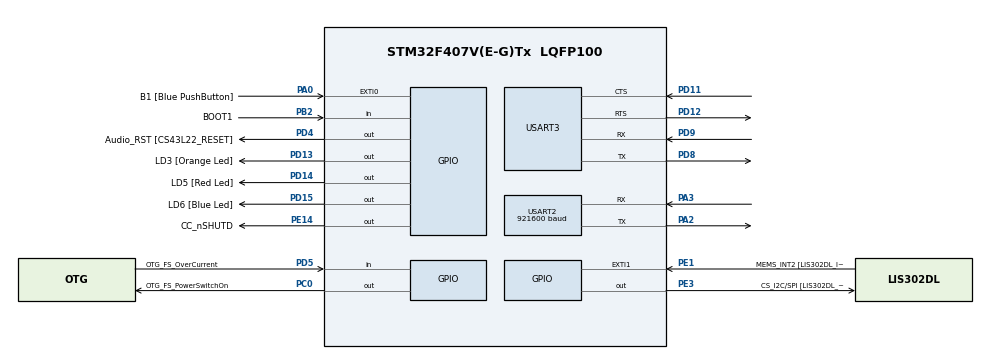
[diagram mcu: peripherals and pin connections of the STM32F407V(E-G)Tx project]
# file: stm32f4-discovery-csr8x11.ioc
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Dma.Request0=USART3_RX
Dma.Request1=USART3_TX
Dma.USART3_RX.0.Direction=DMA_PERIPH_TO_MEMORY
Dma.USART3_RX.0.FIFOMode=DMA_FIFOMODE_DISABLE
Dma.USART3_RX.0.Instance=DMA1_Stream1
Dma.USART3_RX.0.MemDataAlignment=DMA_MDATAALIGN_BYTE
Dma.USART3_RX.0.MemInc=DMA_MINC_ENABLE
Dma.USART3_RX.0.Mode=DMA_NORMAL
Dma.USART3_RX.0.PeriphDataAlignment=DMA_PDATAALIGN_BYTE
Dma.USART3_RX.0.PeriphInc=DMA_PINC_DISABLE
Dma.USART3_RX.0.Priority=DMA_PRIORITY_VERY_HIGH
Dma.USART3_TX.1.Direction=DMA_MEMORY_TO_PERIPH
Dma.USART3_TX.1.FIFOMode=DMA_FIFOMODE_DISABLE
Dma.USART3_TX.1.Instance=DMA1_Stream4
Dma.USART3_TX.1.MemDataAlignment=DMA_MDATAALIGN_BYTE
Dma.USART3_TX.1.MemInc=DMA_MINC_ENABLE
Dma.USART3_TX.1.Mode=DMA_NORMAL
Dma.USART3_TX.1.PeriphDataAlignment=DMA_PDATAALIGN_BYTE
Dma.USART3_TX.1.PeriphInc=DMA_PINC_DISABLE
Dma.USART3_TX.1.Priority=DMA_PRIORITY_MEDIUM
Mcu.Family=STM32F4
Mcu.Name=STM32F407V(E-G)Tx
Mcu.Package=LQFP100
NVIC.DMA1_Stream1_IRQn=true\:0\:0\:true\:false\:true\:true\:true
NVIC.DMA1_Stream4_IRQn=true\:0\:0\:false\:false\:true\:false\:true
NVIC.PriorityGroup=NVIC_PRIORITYGROUP_4
NVIC.USART2_IRQn=true\:15\:0\:true\:false\:true\:true\:true
NVIC.USART3_IRQn=true\:1\:0\:true\:false\:true\:true\:true
PA0-WKUP.GPIO_Label=B1 [Blue PushButton]
PA0-WKUP.GPIO_ModeDefaultEXTI=GPIO_MODE_EVT_RISING
PA0-WKUP.GPIO_PuPd=GPIO_NOPULL
PA0-WKUP.Signal=GPXTI0
PA10.GPIO_Label=OTG_FS_ID
PA10.GPIO_Mode=GPIO_MODE_AF_PP
PA10.GPIO_PuPd=GPIO_NOPULL
PA10.GPIO_Speed=GPIO_SPEED_FREQ_LOW
PA10.Signal=USB_OTG_FS_ID
PA11.GPIO_Label=OTG_FS_DM
PA11.GPIO_Mode=GPIO_MODE_AF_PP
PA11.GPIO_PuPd=GPIO_NOPULL
PA11.GPIO_Speed=GPIO_SPEED_FREQ_LOW
PA11.Signal=USB_OTG_FS_DM
PA12.GPIO_Label=OTG_FS_DP
PA12.GPIO_Mode=GPIO_MODE_AF_PP
PA12.GPIO_PuPd=GPIO_NOPULL
PA12.GPIO_Speed=GPIO_SPEED_FREQ_LOW
PA12.Signal=USB_OTG_FS_DP
PA13.GPIO_Label=SWDIO
PA13.Signal=SYS_JTMS-SWDIO
PA14.GPIO_Label=SWCLK
PA14.Signal=SYS_JTCK-SWCLK
PA2.Mode=Asynchronous
PA2.Signal=USART2_TX
PA3.Mode=Asynchronous
PA3.Signal=USART2_RX
PA4.GPIO_Label=I2S3_WS [CS43L22_LRCK]
PA4.GPIO_Mode=GPIO_MODE_AF_PP
PA4.GPIO_PuPd=GPIO_NOPULL
PA4.GPIO_Speed=GPIO_SPEED_FREQ_LOW
PA4.Signal=I2S3_WS
PA5.GPIO_Label=SPI1_SCK [LIS302DL_SCL/SPC]
PA5.GPIO_Mode=GPIO_MODE_AF_PP
PA5.GPIO_PuPd=GPIO_NOPULL
PA5.GPIO_Speed=GPIO_SPEED_FREQ_LOW
PA5.Signal=SPI1_SCK
PA6.GPIO_Label=SPI1_MISO [LIS302DL_SDO]
PA6.GPIO_Mode=GPIO_MODE_AF_PP
PA6.GPIO_PuPd=GPIO_NOPULL
PA6.GPIO_Speed=GPIO_SPEED_FREQ_LOW
PA6.Signal=SPI1_MISO
PA7.GPIO_Label=SPI1_MOSI [LIS302DL_SDA/SDI/SDO]
PA7.GPIO_Mode=GPIO_MODE_AF_PP
PA7.GPIO_PuPd=GPIO_NOPULL
PA7.GPIO_Speed=GPIO_SPEED_FREQ_LOW
PA7.Signal=SPI1_MOSI
PA9.GPIO_Label=VBUS_FS
PA9.GPIO_Mode=GPIO_MODE_INPUT
PA9.GPIO_PuPd=GPIO_NOPULL
PA9.Signal=USB_OTG_FS_VBUS
PB10.GPIO_Label=CLK_IN [MP45DT02_CLK]
PB10.GPIO_Mode=GPIO_MODE_AF_PP
PB10.GPIO_PuPd=GPIO_NOPULL
PB10.GPIO_Speed=GPIO_SPEED_FREQ_LOW
PB10.Signal=I2S2_CK
PB2.GPIO_Label=BOOT1
PB2.GPIO_Mode=GPIO_MODE_INPUT
PB2.GPIO_PuPd=GPIO_NOPULL
PB2.Signal=GPIO_Input
PB3.GPIO_Label=SWO
PB3.Signal=SYS_JTDO-SWO
PB6.GPIO_Label=Audio_SCL [CS43L22_SCL]
PB6.GPIO_Mode=GPIO_MODE_AF_OD
PB6.GPIO_PuPd=GPIO_NOPULL
PB6.GPIO_Speed=GPIO_SPEED_FREQ_LOW
PB6.Signal=I2C1_SCL
PB9.GPIO_Label=Audio_SDA [CS43L22_SDA]
PB9.GPIO_Mode=GPIO_MODE_AF_OD
PB9.GPIO_PuPd=GPIO_NOPULL
PB9.GPIO_Speed=GPIO_SPEED_FREQ_LOW
PB9.Signal=I2C1_SDA
PC0.GPIO_Label=OTG_FS_PowerSwitchOn
PC0.GPIO_PuPd=GPIO_NOPULL
PC0.GPIO_Speed=GPIO_SPEED_FREQ_LOW
PC0.Signal=GPIO_Output
PC10.GPIO_Label=I2S3_SCK [CS43L22_SCLK]
PC10.GPIO_Mode=GPIO_MODE_AF_PP
PC10.GPIO_PuPd=GPIO_NOPULL
PC10.GPIO_Speed=GPIO_SPEED_FREQ_LOW
PC10.Signal=I2S3_CK
PC12.GPIO_Label=I2S3_SD [CS43L22_SDIN]
PC12.GPIO_Mode=GPIO_MODE_AF_PP
PC12.GPIO_PuPd=GPIO_NOPULL
PC12.GPIO_Speed=GPIO_SPEED_FREQ_LOW
PC12.Signal=I2S3_SD
PC14-OSC32_IN.GPIO_Label=PC14-OSC32_IN
PC14-OSC32_IN.Signal=RCC_OSC32_IN
PC15-OSC32_OUT.GPIO_Label=PC15-OSC32_OUT
PC15-OSC32_OUT.Signal=RCC_OSC32_OUT
PC3.GPIO_Label=PDM_OUT [MP45DT02_DOUT]
PC3.GPIO_Mode=GPIO_MODE_AF_PP
PC3.GPIO_PuPd=GPIO_NOPULL
PC3.GPIO_Speed=GPIO_SPEED_FREQ_LOW
PC3.Signal=I2S2_SD
PC7.GPIO_Label=I2S3_MCK [CS43L22_MCLK]
PC7.GPIO_Mode=GPIO_MODE_AF_PP
PC7.GPIO_PuPd=GPIO_NOPULL
PC7.GPIO_Speed=GPIO_SPEED_FREQ_LOW
PC7.Signal=I2S3_MCK
PD11.Mode=CTS_RTS
PD11.Signal=USART3_CTS
PD12.Mode=CTS_RTS
PD12.Signal=USART3_RTS
PD13.GPIO_Label=LD3 [Orange Led]
PD13.GPIO_PuPd=GPIO_NOPULL
PD13.GPIO_Speed=GPIO_SPEED_FREQ_LOW
PD13.Signal=GPIO_Output
PD14.GPIO_Label=LD5 [Red Led]
PD14.GPIO_PuPd=GPIO_NOPULL
PD14.GPIO_Speed=GPIO_SPEED_FREQ_LOW
PD14.Signal=GPIO_Output
PD15.GPIO_Label=LD6 [Blue Led]
PD15.GPIO_PuPd=GPIO_NOPULL
PD15.GPIO_Speed=GPIO_SPEED_FREQ_LOW
PD15.Signal=GPIO_Output
PD4.GPIO_Label=Audio_RST [CS43L22_RESET]
PD4.GPIO_PuPd=GPIO_NOPULL
PD4.GPIO_Speed=GPIO_SPEED_FREQ_LOW
PD4.Signal=GPIO_Output
PD5.GPIO_Label=OTG_FS_OverCurrent
PD5.GPIO_Mode=GPIO_MODE_INPUT
PD5.GPIO_PuPd=GPIO_NOPULL
PD5.Signal=GPIO_Input
PD8.Mode=Asynchronous
PD8.Signal=USART3_TX
PD9.Mode=Asynchronous
PD9.Signal=USART3_RX
PE1.GPIO_Label=MEMS_INT2 [LIS302DL_INT2]
PE1.GPIO_ModeDefaultEXTI=GPIO_MODE_EVT_RISING
PE1.GPIO_PuPd=GPIO_NOPULL
PE1.Signal=GPXTI1
PE14.GPIO_Label=CC_nSHUTD
PE14.Signal=GPIO_Output
PE3.GPIO_Label=CS_I2C/SPI [LIS302DL_CS_I2C/SPI]
PE3.GPIO_PuPd=GPIO_NOPULL
PE3.GPIO_Speed=GPIO_SPEED_FREQ_LOW
PE3.Signal=GPIO_Output
PH0-OSC_IN.GPIO_Label=PH0-OSC_IN
PH0-OSC_IN.Mode=HSE-External-Oscillator
PH0-OSC_IN.Signal=RCC_OSC_IN
PH1-OSC_OUT.GPIO_Label=PH1-OSC_OUT
PH1-OSC_OUT.Mode=HSE-External-Oscillator
PH1-OSC_OUT.Signal=RCC_OSC_OUT
ProjectManager.HeapSize=0x200
ProjectManager.StackSize=0x400
ProjectManager.TargetToolchain=Makefile
RCC.48MHZClocksFreq_Value=18285714.285714287
RCC.AHBFreq_Value=64000000
RCC.APB1CLKDivider=RCC_HCLK_DIV2
RCC.APB1Freq_Value=32000000
RCC.APB1TimFreq_Value=64000000
RCC.APB2Freq_Value=64000000
RCC.APB2TimFreq_Value=64000000
RCC.CortexFreq_Value=64000000
RCC.HCLKFreq_Value=64000000
RCC.HSE_VALUE=8000000
RCC.HSI_VALUE=16000000
RCC.PLLM=4
RCC.PLLN=64
RCC.PLLQ=7
RCC.PLLSourceVirtual=RCC_PLLSOURCE_HSE
RCC.SYSCLKFreq_VALUE=64000000
RCC.SYSCLKSource=RCC_SYSCLKSOURCE_PLLCLK
RCC.VCOOutputFreq_Value=128000000
USART2.BaudRate=921600
USART2.VirtualMode=VM_ASYNC
USART3.OverSampling=UART_OVERSAMPLING_8
USART3.VirtualMode=VM_ASYNC
board=STM32F4DISCOVERY

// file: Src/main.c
/* USER CODE BEGIN Header */
/**
  ******************************************************************************
  * @file           : main.c
  * @brief          : Main program body
  ******************************************************************************
  * @attention
  *
  * <h2><center>&copy; Copyright (c) 2019 STMicroelectronics.
  * All rights reserved.</center></h2>
  *
  * This software component is licensed by ST under BSD 3-Clause license,
  * the "License"; You may not use this file except in compliance with the
  * License. You may obtain a copy of the License at:
  *                        opensource.org/licenses/BSD-3-Clause
  *
  ******************************************************************************
  */
/* USER CODE END Header */

#include "main.h"
#include "dma.h"
#include "usart.h"
#include "gpio.h"

/* USER CODE BEGIN Includes */
#include "port.h"
/* USER CODE END Includes */

void SystemClock_Config(void);

int main(void)
{

  /* MCU Configuration--------------------------------------------------------*/

  /* Reset of all peripherals, Initializes the Flash interface and the Systick. */
  HAL_Init();

  /* Configure the system clock */
  SystemClock_Config();

  /* Initialize all configured peripherals */
  MX_GPIO_Init();
  MX_DMA_Init();
  MX_USART2_UART_Init();
  MX_USART3_UART_Init();
  /* USER CODE BEGIN 2 */
  // jump to BTstack port
  port_main();
  /* USER CODE END 2 */

  /* Infinite loop */
  while (1)
  {

  }
}

void SystemClock_Config(void)
{
#if defined(RCC_PLLSOURCE_WITH_HSE)
  RCC_OscInitTypeDef RCC_OscInitStruct = {0};
  RCC_ClkInitTypeDef RCC_ClkInitStruct = {0};

  /** Configure the main internal regulator output voltage
  */
  __HAL_RCC_PWR_CLK_ENABLE();
  __HAL_PWR_VOLTAGESCALING_CONFIG(PWR_REGULATOR_VOLTAGE_SCALE1);
  /** Initializes the CPU, AHB and APB busses clocks
  */
  RCC_OscInitStruct.OscillatorType = RCC_OSCILLATORTYPE_HSE;
  RCC_OscInitStruct.HSEState = RCC_HSE_ON;
  RCC_OscInitStruct.PLL.PLLState = RCC_PLL_ON;
  RCC_OscInitStruct.PLL.PLLSource = RCC_PLLSOURCE_HSE;
  RCC_OscInitStruct.PLL.PLLM = 4;
  RCC_OscInitStruct.PLL.PLLN = 168;
  RCC_OscInitStruct.PLL.PLLP = RCC_PLLP_DIV2;
  RCC_OscInitStruct.PLL.PLLQ = 4;
  if (HAL_RCC_OscConfig(&RCC_OscInitStruct) != HAL_OK)
  {
    Error_Handler();
  }
  /** Initializes the CPU, AHB and APB busses clocks
  */
  RCC_ClkInitStruct.ClockType = RCC_CLOCKTYPE_HCLK|RCC_CLOCKTYPE_SYSCLK
                              |RCC_CLOCKTYPE_PCLK1|RCC_CLOCKTYPE_PCLK2;
  RCC_ClkInitStruct.SYSCLKSource = RCC_SYSCLKSOURCE_PLLCLK;
  RCC_ClkInitStruct.AHBCLKDivider = RCC_SYSCLK_DIV1;
  RCC_ClkInitStruct.APB1CLKDivider = RCC_HCLK_DIV4;
  RCC_ClkInitStruct.APB2CLKDivider = RCC_HCLK_DIV2;

  if (HAL_RCC_ClockConfig(&RCC_ClkInitStruct, FLASH_LATENCY_5) != HAL_OK)
  {
    Error_Handler();
  }
#elif defined(RCC_PLLSOURCE_WITH_HSI)
  RCC_OscInitTypeDef RCC_OscInitStruct = {0};
  RCC_ClkInitTypeDef RCC_ClkInitStruct = {0};

  /** Configure the main internal regulator output voltage
  */
  __HAL_RCC_PWR_CLK_ENABLE();
  __HAL_PWR_VOLTAGESCALING_CONFIG(PWR_REGULATOR_VOLTAGE_SCALE1);
  /** Initializes the RCC Oscillators according to the specified parameters
  * in the RCC_OscInitTypeDef structure.
  */
  RCC_OscInitStruct.OscillatorType = RCC_OSCILLATORTYPE_HSI;
  RCC_OscInitStruct.HSIState = RCC_HSI_ON;
  RCC_OscInitStruct.HSICalibrationValue = RCC_HSICALIBRATION_DEFAULT;
  RCC_OscInitStruct.PLL.PLLState = RCC_PLL_ON;
  RCC_OscInitStruct.PLL.PLLSource = RCC_PLLSOURCE_HSI;
  RCC_OscInitStruct.PLL.PLLM = 8;
  RCC_OscInitStruct.PLL.PLLN = 64;
  RCC_OscInitStruct.PLL.PLLP = RCC_PLLP_DIV2;
  RCC_OscInitStruct.PLL.PLLQ = 7;
  if (HAL_RCC_OscConfig(&RCC_OscInitStruct) != HAL_OK)
  {
    Error_Handler();
  }
  /** Initializes the CPU, AHB and APB buses clocks
  */
  RCC_ClkInitStruct.ClockType = RCC_CLOCKTYPE_HCLK|RCC_CLOCKTYPE_SYSCLK
                              |RCC_CLOCKTYPE_PCLK1|RCC_CLOCKTYPE_PCLK2;
  RCC_ClkInitStruct.SYSCLKSource = RCC_SYSCLKSOURCE_PLLCLK;
  RCC_ClkInitStruct.AHBCLKDivider = RCC_SYSCLK_DIV1;
  RCC_ClkInitStruct.APB1CLKDivider = RCC_HCLK_DIV2;
  RCC_ClkInitStruct.APB2CLKDivider = RCC_HCLK_DIV4;

  if (HAL_RCC_ClockConfig(&RCC_ClkInitStruct, FLASH_LATENCY_2) != HAL_OK)
  {
    Error_Handler();
  }
#endif
}

void Error_Handler(void)
{
    printf("enter error handler!");
    while(1);
}

void HardFault_Handler(void)
{
    printf("HardFault_Handler\n");
    while(1);
}

/************************ (C) COPYRIGHT STMicroelectronics *****END OF FILE****/
